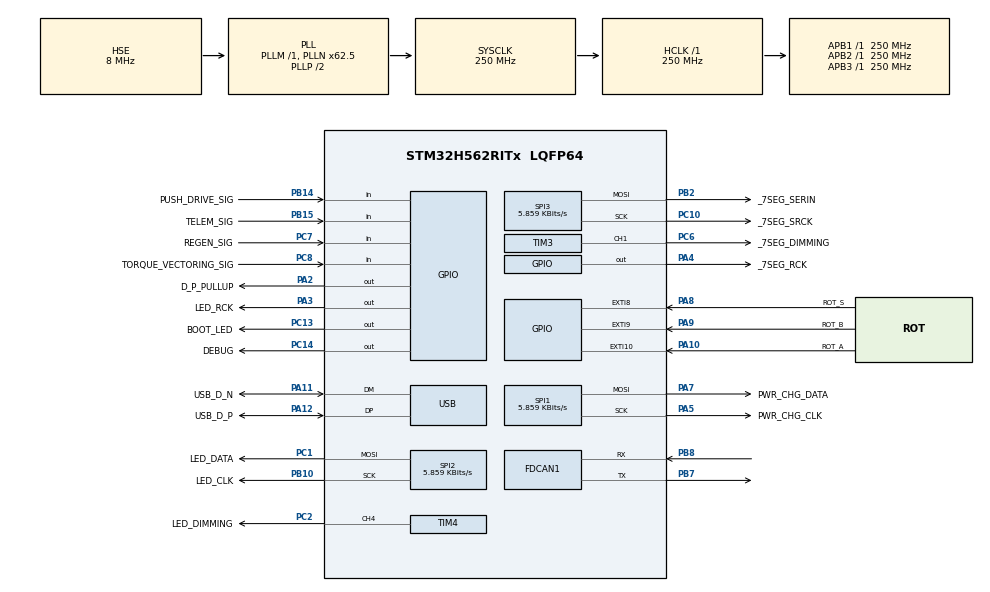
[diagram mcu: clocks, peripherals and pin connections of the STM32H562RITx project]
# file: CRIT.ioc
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BOOTPATH.BootPathName=LEGACY
BOOTPATH.UserSelectedBootPath=LEGACY
CORTEX_M33_NS.userName=CORTEX_M33
FDCAN1.AutoRetransmission=ENABLE
FDCAN1.CalculateBaudRateNominal=1000000
FDCAN1.CalculateTimeBitNominal=1000
FDCAN1.CalculateTimeQuantumNominal=62.5
FDCAN1.DataPrescaler=3
FDCAN1.DataSyncJumpWidth=2
FDCAN1.DataTimeSeg1=5
FDCAN1.DataTimeSeg2=2
FDCAN1.ExtFiltersNbr=1
FDCAN1.FrameFormat=FDCAN_FRAME_FD_NO_BRS
FDCAN1.NominalPrescaler=6
FDCAN1.NominalSyncJumpWidth=2
FDCAN1.NominalTimeSeg1=13
FDCAN1.NominalTimeSeg2=2
FDCAN1.StdFiltersNbr=1
IWDG.Reload=LSI_FREQUENCY/IWDG_PRESCALER/IWDG_RESET_FREQUENCY
Mcu.Family=STM32H5
Mcu.Name=STM32H562RITx
Mcu.Package=LQFP64
Mcu.UserConstants=PWM_TIMER_FREQUENCY,4000;PWM_TIMER_PSC,250;PWM_TIMER_ARR,PWM_TIMER_CLK/(PWM_TIMER_FREQUENCY*PWM_TIMER_PSC);PWM_TIMER_CLK,250000000;IWDG_RESET_FREQUENCY,5;IWDG_PRESCALER,4;LSI_FREQUENCY,32000
NVIC.EXTI10_IRQn=true\:5\:0\:true\:false\:true\:true\:true\:true
NVIC.EXTI8_IRQn=true\:5\:0\:true\:false\:true\:true\:true\:true
NVIC.EXTI9_IRQn=true\:5\:0\:true\:false\:true\:true\:true\:true
NVIC.FDCAN1_IT0_IRQn=true\:5\:0\:true\:false\:true\:true\:true\:true
NVIC.FDCAN1_IT1_IRQn=true\:5\:0\:true\:false\:true\:true\:true\:true
NVIC.PriorityGroup=NVIC_PRIORITYGROUP_4
NVIC.SPI1_IRQn=true\:5\:0\:true\:false\:true\:true\:true\:true
NVIC.SPI2_IRQn=true\:5\:0\:true\:false\:true\:true\:true\:true
NVIC.SPI3_IRQn=true\:5\:0\:true\:false\:true\:true\:true\:true
NVIC.TIM3_IRQn=true\:5\:0\:true\:false\:true\:true\:true\:true
NVIC.TIM4_IRQn=true\:5\:0\:true\:false\:true\:true\:true\:true
NVIC.TIM6_IRQn=true\:15\:0\:false\:false\:true\:false\:true\:true
NVIC.TIM7_IRQn=true\:5\:0\:true\:false\:true\:true\:true\:true
NVIC.TimeBase=TIM6_IRQn
NVIC.TimeBaseIP=TIM6
NVIC.USB_DRD_FS_IRQn=true\:5\:0\:true\:false\:true\:true\:true\:true
PA10.GPIO_Label=ROT_A
PA10.GPIO_ModeDefaultEXTI=GPIO_MODE_IT_RISING_FALLING
PA10.Signal=GPXTI10
PA11.GPIO_Label=USB_D_N
PA11.Mode=Device
PA11.Signal=USB_DM
PA12.GPIO_Label=USB_D_P
PA12.Mode=Device
PA12.Signal=USB_DP
PA13(JTMS/SWDIO).GPIO_Label=SWDIO
PA13(JTMS/SWDIO).Mode=Trace_Asynchronous_SW
PA13(JTMS/SWDIO).Signal=DEBUG_JTMS-SWDIO
PA14(JTCK/SWCLK).GPIO_Label=SWCLK
PA14(JTCK/SWCLK).Mode=Trace_Asynchronous_SW
PA14(JTCK/SWCLK).Signal=DEBUG_JTCK-SWCLK
PA2.GPIO_Label=D_P_PULLUP
PA2.Signal=GPIO_Output
PA3.GPIO_Label=LED_RCK
PA3.Signal=GPIO_Output
PA4.GPIO_Label=_7SEG_RCK
PA4.Signal=GPIO_Output
PA5.GPIO_Label=PWR_CHG_CLK
PA5.GPIO_PuPd=GPIO_PULLDOWN
PA5.Mode=TX_Only_Simplex_Unidirect_Master
PA5.Signal=SPI1_SCK
PA7.GPIO_Label=PWR_CHG_DATA
PA7.GPIO_PuPd=GPIO_PULLDOWN
PA7.Mode=TX_Only_Simplex_Unidirect_Master
PA7.Signal=SPI1_MOSI
PA8.GPIO_Label=ROT_S
PA8.GPIO_ModeDefaultEXTI=GPIO_MODE_IT_RISING
PA8.Signal=GPXTI8
PA9.GPIO_Label=ROT_B
PA9.GPIO_ModeDefaultEXTI=GPIO_MODE_IT_RISING_FALLING
PA9.Signal=GPXTI9
PB10.GPIO_Label=LED_CLK
PB10.GPIO_PuPd=GPIO_PULLDOWN
PB10.Mode=TX_Only_Simplex_Unidirect_Master
PB10.Signal=SPI2_SCK
PB14.GPIO_Label=PUSH_DRIVE_SIG
PB14.Signal=GPIO_Input
PB15.GPIO_Label=TELEM_SIG
PB15.Signal=GPIO_Input
PB2.GPIO_Label=_7SEG_SERIN
PB2.GPIO_PuPd=GPIO_PULLDOWN
PB2.Mode=TX_Only_Simplex_Unidirect_Master
PB2.Signal=SPI3_MOSI
PB3(JTDO/TRACESWO).GPIO_Label=SWO
PB3(JTDO/TRACESWO).Mode=Trace_Asynchronous_SW
PB3(JTDO/TRACESWO).Signal=DEBUG_JTDO-SWO
PB7.Mode=FDCAN_Activate
PB7.Signal=FDCAN1_TX
PB8.Mode=FDCAN_Activate
PB8.Signal=FDCAN1_RX
PC1.GPIO_Label=LED_DATA
PC1.GPIO_PuPd=GPIO_PULLDOWN
PC1.Mode=TX_Only_Simplex_Unidirect_Master
PC1.Signal=SPI2_MOSI
PC10.GPIO_Label=_7SEG_SRCK
PC10.GPIO_PuPd=GPIO_PULLDOWN
PC10.Mode=TX_Only_Simplex_Unidirect_Master
PC10.Signal=SPI3_SCK
PC13.GPIO_Label=BOOT_LED
PC13.Signal=GPIO_Output
PC14-OSC32_IN(OSC32_IN).GPIO_Label=DEBUG
PC14-OSC32_IN(OSC32_IN).GPIO_ModeDefaultOutputPP=GPIO_MODE_OUTPUT_PP
PC14-OSC32_IN(OSC32_IN).Signal=GPIO_Output
PC2.GPIO_Label=LED_DIMMING
PC2.Signal=S_TIM4_CH4
PC6.GPIO_Label=_7SEG_DIMMING
PC6.Signal=S_TIM3_CH1
PC7.GPIO_Label=REGEN_SIG
PC7.GPIO_PuPd=GPIO_PULLUP
PC7.Signal=GPIO_Input
PC8.GPIO_Label=TORQUE_VECTORING_SIG
PC8.GPIO_PuPd=GPIO_PULLUP
PC8.Signal=GPIO_Input
PH0-OSC_IN(PH0).Mode=HSE-External-Oscillator
PH0-OSC_IN(PH0).Signal=RCC_OSC_IN
PH1-OSC_OUT(PH1).Mode=HSE-External-Oscillator
PH1-OSC_OUT(PH1).Signal=RCC_OSC_OUT
ProjectManager.HeapSize=0x200
ProjectManager.StackSize=0x400
ProjectManager.TargetToolchain=CMake
RCC.ADCFreq_Value=250000000
RCC.AHBFreq_Value=250000000
RCC.APB1Freq_Value=250000000
RCC.APB1TimFreq_Value=250000000
RCC.APB2Freq_Value=250000000
RCC.APB2TimFreq_Value=250000000
RCC.APB3Freq_Value=250000000
RCC.CSI_VALUE=4000000
RCC.CortexFreq_Value=250000000
RCC.EPOD_VALUE=8000000
RCC.FDCANClockSelection=RCC_FDCANCLKSOURCE_PLL2Q
RCC.HCLKFreq_Value=250000000
RCC.HSE_VALUE=8000000
RCC.HSI48_VALUE=48000000
RCC.HSI_VALUE=64000000
RCC.LSE_VALUE=32768
RCC.LSIRC_VALUE=32000
RCC.PLL2FRACN=0
RCC.PLL2N=24
RCC.PLL2P=128
RCC.PLL2Source=RCC_PLL2_SOURCE_HSE
RCC.PLL3FRACN=0
RCC.PLL3M=2
RCC.PLL3N=96
RCC.PLL3P=8
RCC.PLL3Q=8
RCC.PLL3Source=RCC_PLL3_SOURCE_HSE
RCC.PLLFRACN=4096
RCC.PLLN=62
RCC.PLLSourceVirtual=RCC_PLL1_SOURCE_HSE
RCC.SPI1CLockSelection=RCC_SPI1CLKSOURCE_PLL2P
RCC.SPI2CLockSelection=RCC_SPI2CLKSOURCE_PLL2P
RCC.SPI3CLockSelection=RCC_SPI3CLKSOURCE_PLL2P
RCC.SYSCLKFreq_VALUE=250000000
RCC.SYSCLKSource=RCC_SYSCLKSOURCE_PLLCLK
RCC.USBCLockSelection=RCC_USBCLKSOURCE_PLL3Q
RCC.USBFreq_Value=48000000
RCC.VCOOutputFreq_Value=500000000
SH.S_TIM3_CH1.0=TIM3_CH1,PWM Generation1 CH1
SH.S_TIM4_CH4.0=TIM4_CH4,PWM Generation4 CH4
SPI1.BaudRatePrescaler=SPI_BAUDRATEPRESCALER_256
SPI1.CalculateBaudRate=5.859 KBits/s
SPI1.DataSize=SPI_DATASIZE_8BIT
SPI1.Direction=SPI_DIRECTION_2LINES_TXONLY
SPI1.Mode=SPI_MODE_MASTER
SPI1.VirtualType=VM_MASTER
SPI2.BaudRatePrescaler=SPI_BAUDRATEPRESCALER_256
SPI2.CalculateBaudRate=5.859 KBits/s
SPI2.DataSize=SPI_DATASIZE_8BIT
SPI2.Direction=SPI_DIRECTION_2LINES_TXONLY
SPI2.FirstBit=SPI_FIRSTBIT_MSB
SPI2.Mode=SPI_MODE_MASTER
SPI2.VirtualType=VM_MASTER
SPI3.BaudRatePrescaler=SPI_BAUDRATEPRESCALER_256
SPI3.CalculateBaudRate=5.859 KBits/s
SPI3.DataSize=SPI_DATASIZE_8BIT
SPI3.Direction=SPI_DIRECTION_2LINES_TXONLY
SPI3.FirstBit=SPI_FIRSTBIT_MSB
SPI3.Mode=SPI_MODE_MASTER
SPI3.VirtualType=VM_MASTER
TIM3.AutoReloadPreload=TIM_AUTORELOAD_PRELOAD_ENABLE
TIM3.Channel-PWM\ Generation1\ CH1=TIM_CHANNEL_1
TIM3.PeriodNoDither=PWM_TIMER_ARR
TIM3.Prescaler=PWM_TIMER_PSC
TIM4.AutoReloadPreload=TIM_AUTORELOAD_PRELOAD_ENABLE
TIM4.Channel-PWM\ Generation4\ CH4=TIM_CHANNEL_4
TIM4.PeriodNoDither=PWM_TIMER_ARR
TIM4.Prescaler=PWM_TIMER_PSC
TIM7.PeriodNoDither=960-1
TIM7.Prescaler=10-1
USB.VirtualMode=Device_Only
VP_BOOTPATH_VS_BOOTPATH.Mode=BP_Activate
VP_CORTEX_M33_NS_VS_Hclk.Mode=Hclk_Mode
VP_IWDG_VS_IWDG.Mode=IWDG_Activate
VP_MEMORYMAP_VS_MEMORYMAP.Mode=CurAppReg
VP_PWR_VS_LPOM.Mode=PowerOptimisation
VP_PWR_VS_SECSignals.Mode=Security/Privilege
VP_SYS_VS_tim6.Mode=TIM6
VP_TIM7_VS_ClockSourceINT.Mode=Enable_Timer
board=custom

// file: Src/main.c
/* USER CODE BEGIN Header */
/**
 ******************************************************************************
 * @file           : main.c
 * @brief          : Main program body
 ******************************************************************************
 * @attention
 *
 * Copyright (c) 2026 STMicroelectronics.
 * All rights reserved.
 *
 * This software is licensed under terms that can be found in the LICENSE file
 * in the root directory of this software component.
 * If no LICENSE file comes with this software, it is provided AS-IS.
 *
 ******************************************************************************
 */
/* USER CODE END Header */
#include "main.h"

/* USER CODE BEGIN Includes */
#include "tasks.h"
#include "hw_error.hpp"
/* USER CODE END Includes */

FDCAN_HandleTypeDef hfdcan1;

IWDG_HandleTypeDef hiwdg;

SPI_HandleTypeDef hspi1;
SPI_HandleTypeDef hspi2;
SPI_HandleTypeDef hspi3;

TIM_HandleTypeDef htim3;
TIM_HandleTypeDef htim4;
TIM_HandleTypeDef htim7;

PCD_HandleTypeDef hpcd_USB_DRD_FS;

void        SystemClock_Config(void);
void        PeriphCommonClock_Config(void);
static void MX_GPIO_Init(void);
static void MX_FDCAN1_Init(void);
static void MX_SPI1_Init(void);
static void MX_SPI2_Init(void);
static void MX_SPI3_Init(void);
static void MX_TIM3_Init(void);
static void MX_TIM4_Init(void);
static void MX_USB_PCD_Init(void);
static void MX_IWDG_Init(void);
static void MX_TIM7_Init(void);

int main(void)
{
    /* USER CODE BEGIN 1 */
    tasks_preInit();
    /* USER CODE END 1 */

    /* MCU Configuration--------------------------------------------------------*/

    /* Reset of all peripherals, Initializes the Flash interface and the Systick. */
    HAL_Init();

    /* Configure the system clock */
    SystemClock_Config();

    /* Configure the peripherals common clocks */
    PeriphCommonClock_Config();

    /* Initialize all configured peripherals */
    MX_GPIO_Init();
    MX_FDCAN1_Init();
    MX_SPI1_Init();
    MX_SPI2_Init();
    MX_SPI3_Init();
    MX_TIM3_Init();
    MX_TIM4_Init();
    MX_USB_PCD_Init();
    MX_IWDG_Init();
    MX_TIM7_Init();
    /* USER CODE BEGIN 2 */
    tasks_init();
    /* USER CODE END 2 */

    /* Infinite loop */
    while (1)
    {

    }
}

void SystemClock_Config(void)
{
    RCC_OscInitTypeDef RCC_OscInitStruct = { 0 };
    RCC_ClkInitTypeDef RCC_ClkInitStruct = { 0 };

    /** Configure the main internal regulator output voltage
     */
    __HAL_PWR_VOLTAGESCALING_CONFIG(PWR_REGULATOR_VOLTAGE_SCALE0);

    while (!__HAL_PWR_GET_FLAG(PWR_FLAG_VOSRDY))
    {
    }

    /** Initializes the RCC Oscillators according to the specified parameters
     * in the RCC_OscInitTypeDef structure.
     */
    RCC_OscInitStruct.OscillatorType = RCC_OSCILLATORTYPE_LSI | RCC_OSCILLATORTYPE_HSE;
    RCC_OscInitStruct.HSEState       = RCC_HSE_ON;
    RCC_OscInitStruct.LSIState       = RCC_LSI_ON;
    RCC_OscInitStruct.PLL.PLLState   = RCC_PLL_ON;
    RCC_OscInitStruct.PLL.PLLSource  = RCC_PLL1_SOURCE_HSE;
    RCC_OscInitStruct.PLL.PLLM       = 1;
    RCC_OscInitStruct.PLL.PLLN       = 62;
    RCC_OscInitStruct.PLL.PLLP       = 2;
    RCC_OscInitStruct.PLL.PLLQ       = 2;
    RCC_OscInitStruct.PLL.PLLR       = 2;
    RCC_OscInitStruct.PLL.PLLRGE     = RCC_PLL1_VCIRANGE_3;
    RCC_OscInitStruct.PLL.PLLVCOSEL  = RCC_PLL1_VCORANGE_WIDE;
    RCC_OscInitStruct.PLL.PLLFRACN   = 4096;
    if (HAL_RCC_OscConfig(&RCC_OscInitStruct) != HAL_OK)
    {
        Error_Handler();
    }

    /** Initializes the CPU, AHB and APB buses clocks
     */
    RCC_ClkInitStruct.ClockType =
        RCC_CLOCKTYPE_HCLK | RCC_CLOCKTYPE_SYSCLK | RCC_CLOCKTYPE_PCLK1 | RCC_CLOCKTYPE_PCLK2 | RCC_CLOCKTYPE_PCLK3;
    RCC_ClkInitStruct.SYSCLKSource   = RCC_SYSCLKSOURCE_PLLCLK;
    RCC_ClkInitStruct.AHBCLKDivider  = RCC_SYSCLK_DIV1;
    RCC_ClkInitStruct.APB1CLKDivider = RCC_HCLK_DIV1;
    RCC_ClkInitStruct.APB2CLKDivider = RCC_HCLK_DIV1;
    RCC_ClkInitStruct.APB3CLKDivider = RCC_HCLK_DIV1;

    if (HAL_RCC_ClockConfig(&RCC_ClkInitStruct, FLASH_LATENCY_5) != HAL_OK)
    {
        Error_Handler();
    }

    /** Configure the programming delay
     */
    __HAL_FLASH_SET_PROGRAM_DELAY(FLASH_PROGRAMMING_DELAY_2);
}

void PeriphCommonClock_Config(void)
{
    RCC_PeriphCLKInitTypeDef PeriphClkInitStruct = { 0 };

    /** Initializes the peripherals clock
     */
    PeriphClkInitStruct.PeriphClockSelection =
        RCC_PERIPHCLK_FDCAN | RCC_PERIPHCLK_SPI1 | RCC_PERIPHCLK_SPI2 | RCC_PERIPHCLK_SPI3;
    PeriphClkInitStruct.PLL2.PLL2Source     = RCC_PLL2_SOURCE_HSE;
    PeriphClkInitStruct.PLL2.PLL2M          = 1;
    PeriphClkInitStruct.PLL2.PLL2N          = 24;
    PeriphClkInitStruct.PLL2.PLL2P          = 128;
    PeriphClkInitStruct.PLL2.PLL2Q          = 2;
    PeriphClkInitStruct.PLL2.PLL2R          = 2;
    PeriphClkInitStruct.PLL2.PLL2RGE        = RCC_PLL2_VCIRANGE_3;
    PeriphClkInitStruct.PLL2.PLL2VCOSEL     = RCC_PLL2_VCORANGE_WIDE;
    PeriphClkInitStruct.PLL2.PLL2FRACN      = 0;
    PeriphClkInitStruct.PLL2.PLL2ClockOut   = RCC_PLL2_DIVP | RCC_PLL2_DIVQ;
    PeriphClkInitStruct.FdcanClockSelection = RCC_FDCANCLKSOURCE_PLL2Q;
    PeriphClkInitStruct.Spi1ClockSelection  = RCC_SPI1CLKSOURCE_PLL2P;
    PeriphClkInitStruct.Spi2ClockSelection  = RCC_SPI2CLKSOURCE_PLL2P;
    PeriphClkInitStruct.Spi3ClockSelection  = RCC_SPI3CLKSOURCE_PLL2P;
    if (HAL_RCCEx_PeriphCLKConfig(&PeriphClkInitStruct) != HAL_OK)
    {
        Error_Handler();
    }
}

static void MX_FDCAN1_Init(void)
{

    hfdcan1.Instance                  = FDCAN1;
    hfdcan1.Init.ClockDivider         = FDCAN_CLOCK_DIV1;
    hfdcan1.Init.FrameFormat          = FDCAN_FRAME_FD_NO_BRS;
    hfdcan1.Init.Mode                 = FDCAN_MODE_NORMAL;
    hfdcan1.Init.AutoRetransmission   = ENABLE;
    hfdcan1.Init.TransmitPause        = DISABLE;
    hfdcan1.Init.ProtocolException    = DISABLE;
    hfdcan1.Init.NominalPrescaler     = 6;
    hfdcan1.Init.NominalSyncJumpWidth = 2;
    hfdcan1.Init.NominalTimeSeg1      = 13;
    hfdcan1.Init.NominalTimeSeg2      = 2;
    hfdcan1.Init.DataPrescaler        = 3;
    hfdcan1.Init.DataSyncJumpWidth    = 2;
    hfdcan1.Init.DataTimeSeg1         = 5;
    hfdcan1.Init.DataTimeSeg2         = 2;
    hfdcan1.Init.StdFiltersNbr        = 1;
    hfdcan1.Init.ExtFiltersNbr        = 1;
    hfdcan1.Init.TxFifoQueueMode      = FDCAN_TX_FIFO_OPERATION;
    if (HAL_FDCAN_Init(&hfdcan1) != HAL_OK)
    {
        Error_Handler();
    }
}

static void MX_IWDG_Init(void)
{

    /* USER CODE BEGIN IWDG_Init 1 */
#ifndef WATCHDOG_DISABLED
    /* USER CODE END IWDG_Init 1 */
    hiwdg.Instance       = IWDG;
    hiwdg.Init.Prescaler = IWDG_PRESCALER_4;
    hiwdg.Init.Window    = 4095;
    hiwdg.Init.Reload    = LSI_FREQUENCY / IWDG_PRESCALER / IWDG_RESET_FREQUENCY;
    hiwdg.Init.EWI       = 0;
    if (HAL_IWDG_Init(&hiwdg) != HAL_OK)
    {
        Error_Handler();
    }
    /* USER CODE BEGIN IWDG_Init 2 */
#endif
    /* USER CODE END IWDG_Init 2 */
}

static void MX_SPI1_Init(void)
{

    /* SPI1 parameter configuration*/
    hspi1.Instance                     = SPI1;
    hspi1.Init.Mode                    = SPI_MODE_MASTER;
    hspi1.Init.Direction               = SPI_DIRECTION_2LINES_TXONLY;
    hspi1.Init.DataSize                = SPI_DATASIZE_8BIT;
    hspi1.Init.CLKPolarity             = SPI_POLARITY_LOW;
    hspi1.Init.CLKPhase                = SPI_PHASE_1EDGE;
    hspi1.Init.NSS                     = SPI_NSS_SOFT;
    hspi1.Init.BaudRatePrescaler       = SPI_BAUDRATEPRESCALER_256;
    hspi1.Init.FirstBit                = SPI_FIRSTBIT_MSB;
    hspi1.Init.TIMode                  = SPI_TIMODE_DISABLE;
    hspi1.Init.CRCCalculation          = SPI_CRCCALCULATION_DISABLE;
    hspi1.Init.CRCPolynomial           = 0x7;
    hspi1.Init.NSSPMode                = SPI_NSS_PULSE_ENABLE;
    hspi1.Init.NSSPolarity             = SPI_NSS_POLARITY_LOW;
    hspi1.Init.FifoThreshold           = SPI_FIFO_THRESHOLD_01DATA;
    hspi1.Init.MasterSSIdleness        = SPI_MASTER_SS_IDLENESS_00CYCLE;
    hspi1.Init.MasterInterDataIdleness = SPI_MASTER_INTERDATA_IDLENESS_00CYCLE;
    hspi1.Init.MasterReceiverAutoSusp  = SPI_MASTER_RX_AUTOSUSP_DISABLE;
    hspi1.Init.MasterKeepIOState       = SPI_MASTER_KEEP_IO_STATE_DISABLE;
    hspi1.Init.IOSwap                  = SPI_IO_SWAP_DISABLE;
    hspi1.Init.ReadyMasterManagement   = SPI_RDY_MASTER_MANAGEMENT_INTERNALLY;
    hspi1.Init.ReadyPolarity           = SPI_RDY_POLARITY_HIGH;
    if (HAL_SPI_Init(&hspi1) != HAL_OK)
    {
        Error_Handler();
    }
}

static void MX_SPI2_Init(void)
{

    /* SPI2 parameter configuration*/
    hspi2.Instance                     = SPI2;
    hspi2.Init.Mode                    = SPI_MODE_MASTER;
    hspi2.Init.Direction               = SPI_DIRECTION_2LINES_TXONLY;
    hspi2.Init.DataSize                = SPI_DATASIZE_8BIT;
    hspi2.Init.CLKPolarity             = SPI_POLARITY_LOW;
    hspi2.Init.CLKPhase                = SPI_PHASE_1EDGE;
    hspi2.Init.NSS                     = SPI_NSS_SOFT;
    hspi2.Init.BaudRatePrescaler       = SPI_BAUDRATEPRESCALER_256;
    hspi2.Init.FirstBit                = SPI_FIRSTBIT_MSB;
    hspi2.Init.TIMode                  = SPI_TIMODE_DISABLE;
    hspi2.Init.CRCCalculation          = SPI_CRCCALCULATION_DISABLE;
    hspi2.Init.CRCPolynomial           = 0x7;
    hspi2.Init.NSSPMode                = SPI_NSS_PULSE_ENABLE;
    hspi2.Init.NSSPolarity             = SPI_NSS_POLARITY_LOW;
    hspi2.Init.FifoThreshold           = SPI_FIFO_THRESHOLD_01DATA;
    hspi2.Init.MasterSSIdleness        = SPI_MASTER_SS_IDLENESS_00CYCLE;
    hspi2.Init.MasterInterDataIdleness = SPI_MASTER_INTERDATA_IDLENESS_00CYCLE;
    hspi2.Init.MasterReceiverAutoSusp  = SPI_MASTER_RX_AUTOSUSP_DISABLE;
    hspi2.Init.MasterKeepIOState       = SPI_MASTER_KEEP_IO_STATE_DISABLE;
    hspi2.Init.IOSwap                  = SPI_IO_SWAP_DISABLE;
    hspi2.Init.ReadyMasterManagement   = SPI_RDY_MASTER_MANAGEMENT_INTERNALLY;
    hspi2.Init.ReadyPolarity           = SPI_RDY_POLARITY_HIGH;
    if (HAL_SPI_Init(&hspi2) != HAL_OK)
    {
        Error_Handler();
    }
}

static void MX_SPI3_Init(void)
{

    /* SPI3 parameter configuration*/
    hspi3.Instance                     = SPI3;
    hspi3.Init.Mode                    = SPI_MODE_MASTER;
    hspi3.Init.Direction               = SPI_DIRECTION_2LINES_TXONLY;
    hspi3.Init.DataSize                = SPI_DATASIZE_8BIT;
    hspi3.Init.CLKPolarity             = SPI_POLARITY_LOW;
    hspi3.Init.CLKPhase                = SPI_PHASE_1EDGE;
    hspi3.Init.NSS                     = SPI_NSS_SOFT;
    hspi3.Init.BaudRatePrescaler       = SPI_BAUDRATEPRESCALER_256;
    hspi3.Init.FirstBit                = SPI_FIRSTBIT_MSB;
    hspi3.Init.TIMode                  = SPI_TIMODE_DISABLE;
    hspi3.Init.CRCCalculation          = SPI_CRCCALCULATION_DISABLE;
    hspi3.Init.CRCPolynomial           = 0x7;
    hspi3.Init.NSSPMode                = SPI_NSS_PULSE_ENABLE;
    hspi3.Init.NSSPolarity             = SPI_NSS_POLARITY_LOW;
    hspi3.Init.FifoThreshold           = SPI_FIFO_THRESHOLD_01DATA;
    hspi3.Init.MasterSSIdleness        = SPI_MASTER_SS_IDLENESS_00CYCLE;
    hspi3.Init.MasterInterDataIdleness = SPI_MASTER_INTERDATA_IDLENESS_00CYCLE;
    hspi3.Init.MasterReceiverAutoSusp  = SPI_MASTER_RX_AUTOSUSP_DISABLE;
    hspi3.Init.MasterKeepIOState       = SPI_MASTER_KEEP_IO_STATE_DISABLE;
    hspi3.Init.IOSwap                  = SPI_IO_SWAP_DISABLE;
    hspi3.Init.ReadyMasterManagement   = SPI_RDY_MASTER_MANAGEMENT_INTERNALLY;
    hspi3.Init.ReadyPolarity           = SPI_RDY_POLARITY_HIGH;
    if (HAL_SPI_Init(&hspi3) != HAL_OK)
    {
        Error_Handler();
    }
}

static void MX_TIM3_Init(void)
{

    TIM_MasterConfigTypeDef sMasterConfig = { 0 };
    TIM_OC_InitTypeDef      sConfigOC     = { 0 };

    htim3.Instance               = TIM3;
    htim3.Init.Prescaler         = PWM_TIMER_PSC;
    htim3.Init.CounterMode       = TIM_COUNTERMODE_UP;
    htim3.Init.Period            = 250;
    htim3.Init.ClockDivision     = TIM_CLOCKDIVISION_DIV1;
    htim3.Init.AutoReloadPreload = TIM_AUTORELOAD_PRELOAD_ENABLE;
    if (HAL_TIM_PWM_Init(&htim3) != HAL_OK)
    {
        Error_Handler();
    }
    sMasterConfig.MasterOutputTrigger = TIM_TRGO_RESET;
    sMasterConfig.MasterSlaveMode     = TIM_MASTERSLAVEMODE_DISABLE;
    if (HAL_TIMEx_MasterConfigSynchronization(&htim3, &sMasterConfig) != HAL_OK)
    {
        Error_Handler();
    }
    sConfigOC.OCMode     = TIM_OCMODE_PWM1;
    sConfigOC.Pulse      = 0;
    sConfigOC.OCPolarity = TIM_OCPOLARITY_HIGH;
    sConfigOC.OCFastMode = TIM_OCFAST_DISABLE;
    if (HAL_TIM_PWM_ConfigChannel(&htim3, &sConfigOC, TIM_CHANNEL_1) != HAL_OK)
    {
        Error_Handler();
    }
    HAL_TIM_MspPostInit(&htim3);
}

static void MX_TIM4_Init(void)
{

    TIM_MasterConfigTypeDef sMasterConfig = { 0 };
    TIM_OC_InitTypeDef      sConfigOC     = { 0 };

    htim4.Instance               = TIM4;
    htim4.Init.Prescaler         = PWM_TIMER_PSC;
    htim4.Init.CounterMode       = TIM_COUNTERMODE_UP;
    htim4.Init.Period            = 250;
    htim4.Init.ClockDivision     = TIM_CLOCKDIVISION_DIV1;
    htim4.Init.AutoReloadPreload = TIM_AUTORELOAD_PRELOAD_ENABLE;
    if (HAL_TIM_PWM_Init(&htim4) != HAL_OK)
    {
        Error_Handler();
    }
    sMasterConfig.MasterOutputTrigger = TIM_TRGO_RESET;
    sMasterConfig.MasterSlaveMode     = TIM_MASTERSLAVEMODE_DISABLE;
    if (HAL_TIMEx_MasterConfigSynchronization(&htim4, &sMasterConfig) != HAL_OK)
    {
        Error_Handler();
    }
    sConfigOC.OCMode     = TIM_OCMODE_PWM1;
    sConfigOC.Pulse      = 0;
    sConfigOC.OCPolarity = TIM_OCPOLARITY_HIGH;
    sConfigOC.OCFastMode = TIM_OCFAST_DISABLE;
    if (HAL_TIM_PWM_ConfigChannel(&htim4, &sConfigOC, TIM_CHANNEL_4) != HAL_OK)
    {
        Error_Handler();
    }
    HAL_TIM_MspPostInit(&htim4);
}

static void MX_TIM7_Init(void)
{

    TIM_MasterConfigTypeDef sMasterConfig = { 0 };

    htim7.Instance               = TIM7;
    htim7.Init.Prescaler         = 10 - 1;
    htim7.Init.CounterMode       = TIM_COUNTERMODE_UP;
    htim7.Init.Period            = 959;
    htim7.Init.AutoReloadPreload = TIM_AUTORELOAD_PRELOAD_DISABLE;
    if (HAL_TIM_Base_Init(&htim7) != HAL_OK)
    {
        Error_Handler();
    }
    sMasterConfig.MasterOutputTrigger = TIM_TRGO_RESET;
    sMasterConfig.MasterSlaveMode     = TIM_MASTERSLAVEMODE_DISABLE;
    if (HAL_TIMEx_MasterConfigSynchronization(&htim7, &sMasterConfig) != HAL_OK)
    {
        Error_Handler();
    }
}

static void MX_USB_PCD_Init(void)
{

    hpcd_USB_DRD_FS.Instance                      = USB_DRD_FS;
    hpcd_USB_DRD_FS.Init.dev_endpoints            = 8;
    hpcd_USB_DRD_FS.Init.speed                    = USBD_FS_SPEED;
    hpcd_USB_DRD_FS.Init.phy_itface               = PCD_PHY_EMBEDDED;
    hpcd_USB_DRD_FS.Init.Sof_enable               = DISABLE;
    hpcd_USB_DRD_FS.Init.low_power_enable         = DISABLE;
    hpcd_USB_DRD_FS.Init.lpm_enable               = DISABLE;
    hpcd_USB_DRD_FS.Init.battery_charging_enable  = DISABLE;
    hpcd_USB_DRD_FS.Init.vbus_sensing_enable      = DISABLE;
    hpcd_USB_DRD_FS.Init.bulk_doublebuffer_enable = DISABLE;
    hpcd_USB_DRD_FS.Init.iso_singlebuffer_enable  = DISABLE;
    if (HAL_PCD_Init(&hpcd_USB_DRD_FS) != HAL_OK)
    {
        Error_Handler();
    }
}

static void MX_GPIO_Init(void)
{
    GPIO_InitTypeDef GPIO_InitStruct = { 0 };

    /* GPIO Ports Clock Enable */
    __HAL_RCC_GPIOC_CLK_ENABLE();
    __HAL_RCC_GPIOH_CLK_ENABLE();
    __HAL_RCC_GPIOA_CLK_ENABLE();
    __HAL_RCC_GPIOB_CLK_ENABLE();

    /*Configure GPIO pin Output Level */
    HAL_GPIO_WritePin(GPIOC, BOOT_Pin | LED_Pin, GPIO_PIN_RESET);

    /*Configure GPIO pin Output Level */
    HAL_GPIO_WritePin(GPIOA, D_P_PULLUP_Pin | LED_RCK_Pin | _7SEG_RCK_Pin, GPIO_PIN_RESET);

    /*Configure GPIO pins : BOOT_Pin LED_Pin */
    GPIO_InitStruct.Pin   = BOOT_Pin | LED_Pin;
    GPIO_InitStruct.Mode  = GPIO_MODE_OUTPUT_PP;
    GPIO_InitStruct.Pull  = GPIO_NOPULL;
    GPIO_InitStruct.Speed = GPIO_SPEED_FREQ_LOW;
    HAL_GPIO_Init(GPIOC, &GPIO_InitStruct);

    /*Configure GPIO pins : D_P_PULLUP_Pin LED_RCK_Pin _7SEG_RCK_Pin */
    GPIO_InitStruct.Pin   = D_P_PULLUP_Pin | LED_RCK_Pin | _7SEG_RCK_Pin;
    GPIO_InitStruct.Mode  = GPIO_MODE_OUTPUT_PP;
    GPIO_InitStruct.Pull  = GPIO_NOPULL;
    GPIO_InitStruct.Speed = GPIO_SPEED_FREQ_LOW;
    HAL_GPIO_Init(GPIOA, &GPIO_InitStruct);

    /*Configure GPIO pins : PUSH_DRIVE_SIG_Pin TELEM_SIG_Pin */
    GPIO_InitStruct.Pin  = PUSH_DRIVE_SIG_Pin | TELEM_SIG_Pin;
    GPIO_InitStruct.Mode = GPIO_MODE_INPUT;
    GPIO_InitStruct.Pull = GPIO_NOPULL;
    HAL_GPIO_Init(GPIOB, &GPIO_InitStruct);

    /*Configure GPIO pins : REGEN_SIG_Pin TORQUE_VECTORING_SIG_Pin LAUNCH_CONTROL_SIG_Pin */
    GPIO_InitStruct.Pin  = REGEN_SIG_Pin | TORQUE_VECTORING_SIG_Pin | LAUNCH_CONTROL_SIG_Pin;
    GPIO_InitStruct.Mode = GPIO_MODE_INPUT;
    GPIO_InitStruct.Pull = GPIO_NOPULL;
    HAL_GPIO_Init(GPIOC, &GPIO_InitStruct);

    /*Configure GPIO pin : ROT_S_Pin */
    GPIO_InitStruct.Pin  = ROT_S_Pin;
    GPIO_InitStruct.Mode = GPIO_MODE_IT_RISING;
    GPIO_InitStruct.Pull = GPIO_NOPULL;
    HAL_GPIO_Init(ROT_S_GPIO_Port, &GPIO_InitStruct);

    /*Configure GPIO pins : ROT_B_Pin ROT_A_Pin */
    GPIO_InitStruct.Pin  = ROT_B_Pin | ROT_A_Pin;
    GPIO_InitStruct.Mode = GPIO_MODE_IT_RISING_FALLING;
    GPIO_InitStruct.Pull = GPIO_NOPULL;
    HAL_GPIO_Init(GPIOA, &GPIO_InitStruct);

    /* EXTI interrupt init*/
    HAL_NVIC_SetPriority(EXTI8_IRQn, 5, 0);
    HAL_NVIC_EnableIRQ(EXTI8_IRQn);

    HAL_NVIC_SetPriority(EXTI9_IRQn, 5, 0);
    HAL_NVIC_EnableIRQ(EXTI9_IRQn);

    HAL_NVIC_SetPriority(EXTI10_IRQn, 5, 0);
    HAL_NVIC_EnableIRQ(EXTI10_IRQn);

}

void HAL_TIM_PeriodElapsedCallback(TIM_HandleTypeDef *htim)
{
    if (htim->Instance == TIM6)
    {
        HAL_IncTick();
    }
}

void Error_Handler(void)
{
    __disable_irq();
    while (1)
    {
    }
}
